# Generated by FakeRAM 2.0
VERSION 5.7 ;
BUSBITCHARS "[]" ;
PROPERTYDEFINITIONS
  MACRO width INTEGER ;
  MACRO depth INTEGER ;
  MACRO banks INTEGER ;
END PROPERTYDEFINITIONS
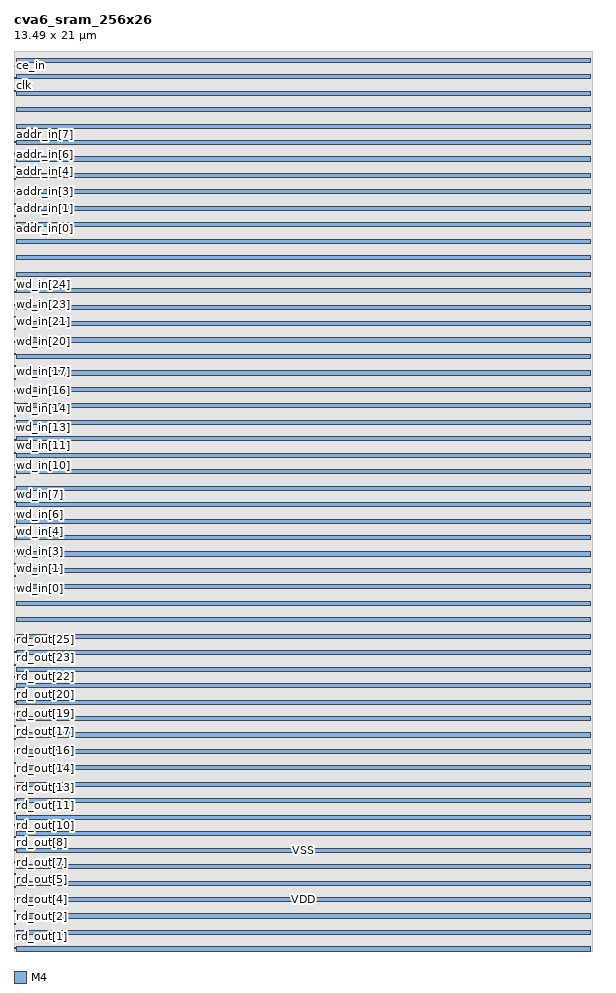
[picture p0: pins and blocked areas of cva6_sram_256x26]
MACRO cva6_sram_256x26
  PROPERTY width 26 ;
  PROPERTY depth 256 ;
  PROPERTY banks 1 ;
  FOREIGN cva6_sram_256x26 0 0 ;
  SYMMETRY X Y R90 ;
  SIZE 13.4900 BY 21.0000 ;
  CLASS BLOCK ;
  PIN rd_out[0]
    DIRECTION OUTPUT ;
    USE SIGNAL ;
    PORT
      LAYER M4 ;
      RECT 0.00000 0.04800 0.02400 0.07200 ;
    END
  END rd_out[0]
  PIN rd_out[1]
    DIRECTION OUTPUT ;
    USE SIGNAL ;
    PORT
      LAYER M4 ;
      RECT 0.00000 0.33600 0.02400 0.36000 ;
    END
  END rd_out[1]
  PIN rd_out[2]
    DIRECTION OUTPUT ;
    USE SIGNAL ;
    PORT
      LAYER M4 ;
      RECT 0.00000 0.62400 0.02400 0.64800 ;
    END
  END rd_out[2]
  PIN rd_out[3]
    DIRECTION OUTPUT ;
    USE SIGNAL ;
    PORT
      LAYER M4 ;
      RECT 0.00000 0.91200 0.02400 0.93600 ;
    END
  END rd_out[3]
  PIN rd_out[4]
    DIRECTION OUTPUT ;
    USE SIGNAL ;
    PORT
      LAYER M4 ;
      RECT 0.00000 1.20000 0.02400 1.22400 ;
    END
  END rd_out[4]
  PIN rd_out[5]
    DIRECTION OUTPUT ;
    USE SIGNAL ;
    PORT
      LAYER M4 ;
      RECT 0.00000 1.48800 0.02400 1.51200 ;
    END
  END rd_out[5]
  PIN rd_out[6]
    DIRECTION OUTPUT ;
    USE SIGNAL ;
    PORT
      LAYER M4 ;
      RECT 0.00000 1.77600 0.02400 1.80000 ;
    END
  END rd_out[6]
  PIN rd_out[7]
    DIRECTION OUTPUT ;
    USE SIGNAL ;
    PORT
      LAYER M4 ;
      RECT 0.00000 2.06400 0.02400 2.08800 ;
    END
  END rd_out[7]
  PIN rd_out[8]
    DIRECTION OUTPUT ;
    USE SIGNAL ;
    PORT
      LAYER M4 ;
      RECT 0.00000 2.35200 0.02400 2.37600 ;
    END
  END rd_out[8]
  PIN rd_out[9]
    DIRECTION OUTPUT ;
    USE SIGNAL ;
    PORT
      LAYER M4 ;
      RECT 0.00000 2.64000 0.02400 2.66400 ;
    END
  END rd_out[9]
  PIN rd_out[10]
    DIRECTION OUTPUT ;
    USE SIGNAL ;
    PORT
      LAYER M4 ;
      RECT 0.00000 2.92800 0.02400 2.95200 ;
    END
  END rd_out[10]
  PIN rd_out[11]
    DIRECTION OUTPUT ;
    USE SIGNAL ;
    PORT
      LAYER M4 ;
      RECT 0.00000 3.21600 0.02400 3.24000 ;
    END
  END rd_out[11]
  PIN rd_out[12]
    DIRECTION OUTPUT ;
    USE SIGNAL ;
    PORT
      LAYER M4 ;
      RECT 0.00000 3.50400 0.02400 3.52800 ;
    END
  END rd_out[12]
  PIN rd_out[13]
    DIRECTION OUTPUT ;
    USE SIGNAL ;
    PORT
      LAYER M4 ;
      RECT 0.00000 3.79200 0.02400 3.81600 ;
    END
  END rd_out[13]
  PIN rd_out[14]
    DIRECTION OUTPUT ;
    USE SIGNAL ;
    PORT
      LAYER M4 ;
      RECT 0.00000 4.08000 0.02400 4.10400 ;
    END
  END rd_out[14]
  PIN rd_out[15]
    DIRECTION OUTPUT ;
    USE SIGNAL ;
    PORT
      LAYER M4 ;
      RECT 0.00000 4.36800 0.02400 4.39200 ;
    END
  END rd_out[15]
  PIN rd_out[16]
    DIRECTION OUTPUT ;
    USE SIGNAL ;
    PORT
      LAYER M4 ;
      RECT 0.00000 4.65600 0.02400 4.68000 ;
    END
  END rd_out[16]
  PIN rd_out[17]
    DIRECTION OUTPUT ;
    USE SIGNAL ;
    PORT
      LAYER M4 ;
      RECT 0.00000 4.94400 0.02400 4.96800 ;
    END
  END rd_out[17]
  PIN rd_out[18]
    DIRECTION OUTPUT ;
    USE SIGNAL ;
    PORT
      LAYER M4 ;
      RECT 0.00000 5.23200 0.02400 5.25600 ;
    END
  END rd_out[18]
  PIN rd_out[19]
    DIRECTION OUTPUT ;
    USE SIGNAL ;
    PORT
      LAYER M4 ;
      RECT 0.00000 5.52000 0.02400 5.54400 ;
    END
  END rd_out[19]
  PIN rd_out[20]
    DIRECTION OUTPUT ;
    USE SIGNAL ;
    PORT
      LAYER M4 ;
      RECT 0.00000 5.80800 0.02400 5.83200 ;
    END
  END rd_out[20]
  PIN rd_out[21]
    DIRECTION OUTPUT ;
    USE SIGNAL ;
    PORT
      LAYER M4 ;
      RECT 0.00000 6.09600 0.02400 6.12000 ;
    END
  END rd_out[21]
  PIN rd_out[22]
    DIRECTION OUTPUT ;
    USE SIGNAL ;
    PORT
      LAYER M4 ;
      RECT 0.00000 6.38400 0.02400 6.40800 ;
    END
  END rd_out[22]
  PIN rd_out[23]
    DIRECTION OUTPUT ;
    USE SIGNAL ;
    PORT
      LAYER M4 ;
      RECT 0.00000 6.67200 0.02400 6.69600 ;
    END
  END rd_out[23]
  PIN rd_out[24]
    DIRECTION OUTPUT ;
    USE SIGNAL ;
    PORT
      LAYER M4 ;
      RECT 0.00000 6.96000 0.02400 6.98400 ;
    END
  END rd_out[24]
  PIN rd_out[25]
    DIRECTION OUTPUT ;
    USE SIGNAL ;
    PORT
      LAYER M4 ;
      RECT 0.00000 7.24800 0.02400 7.27200 ;
    END
  END rd_out[25]
  PIN wd_in[0]
    DIRECTION INPUT ;
    USE SIGNAL ;
    PORT
      LAYER M4 ;
      RECT 0.00000 8.44800 0.02400 8.47200 ;
    END
  END wd_in[0]
  PIN wd_in[1]
    DIRECTION INPUT ;
    USE SIGNAL ;
    PORT
      LAYER M4 ;
      RECT 0.00000 8.73600 0.02400 8.76000 ;
    END
  END wd_in[1]
  PIN wd_in[2]
    DIRECTION INPUT ;
    USE SIGNAL ;
    PORT
      LAYER M4 ;
      RECT 0.00000 9.02400 0.02400 9.04800 ;
    END
  END wd_in[2]
  PIN wd_in[3]
    DIRECTION INPUT ;
    USE SIGNAL ;
    PORT
      LAYER M4 ;
      RECT 0.00000 9.31200 0.02400 9.33600 ;
    END
  END wd_in[3]
  PIN wd_in[4]
    DIRECTION INPUT ;
    USE SIGNAL ;
    PORT
      LAYER M4 ;
      RECT 0.00000 9.60000 0.02400 9.62400 ;
    END
  END wd_in[4]
  PIN wd_in[5]
    DIRECTION INPUT ;
    USE SIGNAL ;
    PORT
      LAYER M4 ;
      RECT 0.00000 9.88800 0.02400 9.91200 ;
    END
  END wd_in[5]
  PIN wd_in[6]
    DIRECTION INPUT ;
    USE SIGNAL ;
    PORT
      LAYER M4 ;
      RECT 0.00000 10.17600 0.02400 10.20000 ;
    END
  END wd_in[6]
  PIN wd_in[7]
    DIRECTION INPUT ;
    USE SIGNAL ;
    PORT
      LAYER M4 ;
      RECT 0.00000 10.46400 0.02400 10.48800 ;
    END
  END wd_in[7]
  PIN wd_in[8]
    DIRECTION INPUT ;
    USE SIGNAL ;
    PORT
      LAYER M4 ;
      RECT 0.00000 10.75200 0.02400 10.77600 ;
    END
  END wd_in[8]
  PIN wd_in[9]
    DIRECTION INPUT ;
    USE SIGNAL ;
    PORT
      LAYER M4 ;
      RECT 0.00000 11.04000 0.02400 11.06400 ;
    END
  END wd_in[9]
  PIN wd_in[10]
    DIRECTION INPUT ;
    USE SIGNAL ;
    PORT
      LAYER M4 ;
      RECT 0.00000 11.32800 0.02400 11.35200 ;
    END
  END wd_in[10]
  PIN wd_in[11]
    DIRECTION INPUT ;
    USE SIGNAL ;
    PORT
      LAYER M4 ;
      RECT 0.00000 11.61600 0.02400 11.64000 ;
    END
  END wd_in[11]
  PIN wd_in[12]
    DIRECTION INPUT ;
    USE SIGNAL ;
    PORT
      LAYER M4 ;
      RECT 0.00000 11.90400 0.02400 11.92800 ;
    END
  END wd_in[12]
  PIN wd_in[13]
    DIRECTION INPUT ;
    USE SIGNAL ;
    PORT
      LAYER M4 ;
      RECT 0.00000 12.19200 0.02400 12.21600 ;
    END
  END wd_in[13]
  PIN wd_in[14]
    DIRECTION INPUT ;
    USE SIGNAL ;
    PORT
      LAYER M4 ;
      RECT 0.00000 12.48000 0.02400 12.50400 ;
    END
  END wd_in[14]
  PIN wd_in[15]
    DIRECTION INPUT ;
    USE SIGNAL ;
    PORT
      LAYER M4 ;
      RECT 0.00000 12.76800 0.02400 12.79200 ;
    END
  END wd_in[15]
  PIN wd_in[16]
    DIRECTION INPUT ;
    USE SIGNAL ;
    PORT
      LAYER M4 ;
      RECT 0.00000 13.05600 0.02400 13.08000 ;
    END
  END wd_in[16]
  PIN wd_in[17]
    DIRECTION INPUT ;
    USE SIGNAL ;
    PORT
      LAYER M4 ;
      RECT 0.00000 13.34400 0.02400 13.36800 ;
    END
  END wd_in[17]
  PIN wd_in[18]
    DIRECTION INPUT ;
    USE SIGNAL ;
    PORT
      LAYER M4 ;
      RECT 0.00000 13.63200 0.02400 13.65600 ;
    END
  END wd_in[18]
  PIN wd_in[19]
    DIRECTION INPUT ;
    USE SIGNAL ;
    PORT
      LAYER M4 ;
      RECT 0.00000 13.92000 0.02400 13.94400 ;
    END
  END wd_in[19]
  PIN wd_in[20]
    DIRECTION INPUT ;
    USE SIGNAL ;
    PORT
      LAYER M4 ;
      RECT 0.00000 14.20800 0.02400 14.23200 ;
    END
  END wd_in[20]
  PIN wd_in[21]
    DIRECTION INPUT ;
    USE SIGNAL ;
    PORT
      LAYER M4 ;
      RECT 0.00000 14.49600 0.02400 14.52000 ;
    END
  END wd_in[21]
  PIN wd_in[22]
    DIRECTION INPUT ;
    USE SIGNAL ;
    PORT
      LAYER M4 ;
      RECT 0.00000 14.78400 0.02400 14.80800 ;
    END
  END wd_in[22]
  PIN wd_in[23]
    DIRECTION INPUT ;
    USE SIGNAL ;
    PORT
      LAYER M4 ;
      RECT 0.00000 15.07200 0.02400 15.09600 ;
    END
  END wd_in[23]
  PIN wd_in[24]
    DIRECTION INPUT ;
    USE SIGNAL ;
    PORT
      LAYER M4 ;
      RECT 0.00000 15.36000 0.02400 15.38400 ;
    END
  END wd_in[24]
  PIN wd_in[25]
    DIRECTION INPUT ;
    USE SIGNAL ;
    PORT
      LAYER M4 ;
      RECT 0.00000 15.64800 0.02400 15.67200 ;
    END
  END wd_in[25]
  PIN addr_in[0]
    DIRECTION INPUT ;
    USE SIGNAL ;
    PORT
      LAYER M4 ;
      RECT 0.00000 16.84800 0.02400 16.87200 ;
    END
  END addr_in[0]
  PIN addr_in[1]
    DIRECTION INPUT ;
    USE SIGNAL ;
    PORT
      LAYER M4 ;
      RECT 0.00000 17.13600 0.02400 17.16000 ;
    END
  END addr_in[1]
  PIN addr_in[2]
    DIRECTION INPUT ;
    USE SIGNAL ;
    PORT
      LAYER M4 ;
      RECT 0.00000 17.42400 0.02400 17.44800 ;
    END
  END addr_in[2]
  PIN addr_in[3]
    DIRECTION INPUT ;
    USE SIGNAL ;
    PORT
      LAYER M4 ;
      RECT 0.00000 17.71200 0.02400 17.73600 ;
    END
  END addr_in[3]
  PIN addr_in[4]
    DIRECTION INPUT ;
    USE SIGNAL ;
    PORT
      LAYER M4 ;
      RECT 0.00000 18.00000 0.02400 18.02400 ;
    END
  END addr_in[4]
  PIN addr_in[5]
    DIRECTION INPUT ;
    USE SIGNAL ;
    PORT
      LAYER M4 ;
      RECT 0.00000 18.28800 0.02400 18.31200 ;
    END
  END addr_in[5]
  PIN addr_in[6]
    DIRECTION INPUT ;
    USE SIGNAL ;
    PORT
      LAYER M4 ;
      RECT 0.00000 18.57600 0.02400 18.60000 ;
    END
  END addr_in[6]
  PIN addr_in[7]
    DIRECTION INPUT ;
    USE SIGNAL ;
    PORT
      LAYER M4 ;
      RECT 0.00000 18.86400 0.02400 18.88800 ;
    END
  END addr_in[7]
  PIN we_in
    DIRECTION INPUT ;
    USE SIGNAL ;
    PORT
      LAYER M4 ;
      RECT 0.00000 20.06400 0.02400 20.08800 ;
    END
  END we_in
  PIN clk
    DIRECTION INPUT ;
    USE SIGNAL ;
    PORT
      LAYER M4 ;
      RECT 0.00000 20.35200 0.02400 20.37600 ;
    END
  END clk
  PIN ce_in
    DIRECTION INPUT ;
    USE SIGNAL ;
    PORT
      LAYER M4 ;
      RECT 0.00000 20.64000 0.02400 20.66400 ;
    END
  END ce_in
  PIN VDD
    DIRECTION INOUT ;
    USE POWER ;
    PORT
      LAYER M4 ;
      RECT 0.04800 0.38400 13.44200 0.48000 ;
      RECT 0.04800 1.15200 13.44200 1.24800 ;
      RECT 0.04800 1.92000 13.44200 2.01600 ;
      RECT 0.04800 2.68800 13.44200 2.78400 ;
      RECT 0.04800 3.45600 13.44200 3.55200 ;
      RECT 0.04800 4.22400 13.44200 4.32000 ;
      RECT 0.04800 4.99200 13.44200 5.08800 ;
      RECT 0.04800 5.76000 13.44200 5.85600 ;
      RECT 0.04800 6.52800 13.44200 6.62400 ;
      RECT 0.04800 7.29600 13.44200 7.39200 ;
      RECT 0.04800 8.06400 13.44200 8.16000 ;
      RECT 0.04800 8.83200 13.44200 8.92800 ;
      RECT 0.04800 9.60000 13.44200 9.69600 ;
      RECT 0.04800 10.36800 13.44200 10.46400 ;
      RECT 0.04800 11.13600 13.44200 11.23200 ;
      RECT 0.04800 11.90400 13.44200 12.00000 ;
      RECT 0.04800 12.67200 13.44200 12.76800 ;
      RECT 0.04800 13.44000 13.44200 13.53600 ;
      RECT 0.04800 14.20800 13.44200 14.30400 ;
      RECT 0.04800 14.97600 13.44200 15.07200 ;
      RECT 0.04800 15.74400 13.44200 15.84000 ;
      RECT 0.04800 16.51200 13.44200 16.60800 ;
      RECT 0.04800 17.28000 13.44200 17.37600 ;
      RECT 0.04800 18.04800 13.44200 18.14400 ;
      RECT 0.04800 18.81600 13.44200 18.91200 ;
      RECT 0.04800 19.58400 13.44200 19.68000 ;
      RECT 0.04800 20.35200 13.44200 20.44800 ;
    END
  END VDD
  PIN VSS
    DIRECTION INOUT ;
    USE GROUND ;
    PORT
      LAYER M4 ;
      RECT 0.04800 0.00000 13.44200 0.09600 ;
      RECT 0.04800 0.76800 13.44200 0.86400 ;
      RECT 0.04800 1.53600 13.44200 1.63200 ;
      RECT 0.04800 2.30400 13.44200 2.40000 ;
      RECT 0.04800 3.07200 13.44200 3.16800 ;
      RECT 0.04800 3.84000 13.44200 3.93600 ;
      RECT 0.04800 4.60800 13.44200 4.70400 ;
      RECT 0.04800 5.37600 13.44200 5.47200 ;
      RECT 0.04800 6.14400 13.44200 6.24000 ;
      RECT 0.04800 6.91200 13.44200 7.00800 ;
      RECT 0.04800 7.68000 13.44200 7.77600 ;
      RECT 0.04800 8.44800 13.44200 8.54400 ;
      RECT 0.04800 9.21600 13.44200 9.31200 ;
      RECT 0.04800 9.98400 13.44200 10.08000 ;
      RECT 0.04800 10.75200 13.44200 10.84800 ;
      RECT 0.04800 11.52000 13.44200 11.61600 ;
      RECT 0.04800 12.28800 13.44200 12.38400 ;
      RECT 0.04800 13.05600 13.44200 13.15200 ;
      RECT 0.04800 13.82400 13.44200 13.92000 ;
      RECT 0.04800 14.59200 13.44200 14.68800 ;
      RECT 0.04800 15.36000 13.44200 15.45600 ;
      RECT 0.04800 16.12800 13.44200 16.22400 ;
      RECT 0.04800 16.89600 13.44200 16.99200 ;
      RECT 0.04800 17.66400 13.44200 17.76000 ;
      RECT 0.04800 18.43200 13.44200 18.52800 ;
      RECT 0.04800 19.20000 13.44200 19.29600 ;
      RECT 0.04800 19.96800 13.44200 20.06400 ;
      RECT 0.04800 20.73600 13.44200 20.83200 ;
    END
  END VSS
  OBS
    LAYER M1 ;
    RECT 0 0 13.49000 21.00000 ;
    LAYER M2 ;
    RECT 0 0 13.49000 21.00000 ;
    LAYER M3 ;
    RECT 0 0 13.49000 21.00000 ;
    LAYER M4 ;
    RECT 0 0 13.49000 21.00000 ;
  END
END cva6_sram_256x26

END LIBRARY
